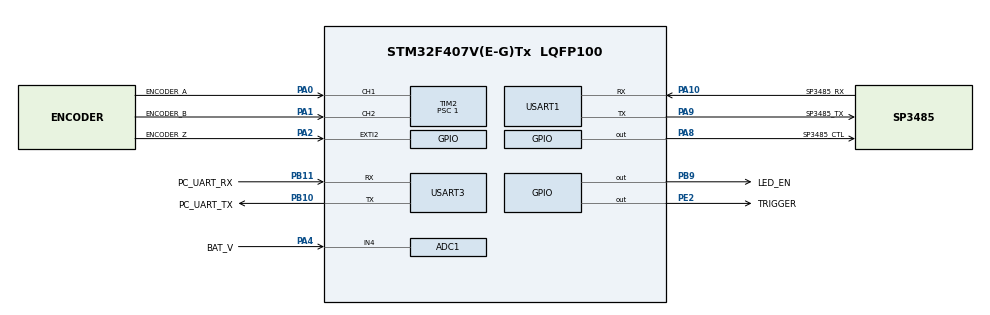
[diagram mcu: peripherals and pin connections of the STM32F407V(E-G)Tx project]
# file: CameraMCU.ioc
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ADC1.Channel-0\#ChannelRegularConversion=ADC_CHANNEL_4
ADC1.NbrOfConversionFlag=1
ADC1.Rank-0\#ChannelRegularConversion=1
ADC1.SamplingTime-0\#ChannelRegularConversion=ADC_SAMPLETIME_3CYCLES
ADC1.master=1
Dma.Request0=USART1_RX
Dma.Request1=USART3_RX
Dma.Request2=USART3_TX
Dma.Request3=USART1_TX
Dma.USART1_RX.0.Direction=DMA_PERIPH_TO_MEMORY
Dma.USART1_RX.0.FIFOMode=DMA_FIFOMODE_DISABLE
Dma.USART1_RX.0.Instance=DMA2_Stream2
Dma.USART1_RX.0.MemDataAlignment=DMA_MDATAALIGN_BYTE
Dma.USART1_RX.0.MemInc=DMA_MINC_ENABLE
Dma.USART1_RX.0.Mode=DMA_NORMAL
Dma.USART1_RX.0.PeriphDataAlignment=DMA_PDATAALIGN_BYTE
Dma.USART1_RX.0.PeriphInc=DMA_PINC_DISABLE
Dma.USART1_RX.0.Priority=DMA_PRIORITY_MEDIUM
Dma.USART1_TX.3.Direction=DMA_MEMORY_TO_PERIPH
Dma.USART1_TX.3.FIFOMode=DMA_FIFOMODE_DISABLE
Dma.USART1_TX.3.Instance=DMA2_Stream7
Dma.USART1_TX.3.MemDataAlignment=DMA_MDATAALIGN_BYTE
Dma.USART1_TX.3.MemInc=DMA_MINC_ENABLE
Dma.USART1_TX.3.Mode=DMA_NORMAL
Dma.USART1_TX.3.PeriphDataAlignment=DMA_PDATAALIGN_BYTE
Dma.USART1_TX.3.PeriphInc=DMA_PINC_DISABLE
Dma.USART1_TX.3.Priority=DMA_PRIORITY_LOW
Dma.USART3_RX.1.Direction=DMA_PERIPH_TO_MEMORY
Dma.USART3_RX.1.FIFOMode=DMA_FIFOMODE_DISABLE
Dma.USART3_RX.1.Instance=DMA1_Stream1
Dma.USART3_RX.1.MemDataAlignment=DMA_MDATAALIGN_BYTE
Dma.USART3_RX.1.MemInc=DMA_MINC_ENABLE
Dma.USART3_RX.1.Mode=DMA_NORMAL
Dma.USART3_RX.1.PeriphDataAlignment=DMA_PDATAALIGN_BYTE
Dma.USART3_RX.1.PeriphInc=DMA_PINC_DISABLE
Dma.USART3_RX.1.Priority=DMA_PRIORITY_LOW
Dma.USART3_TX.2.Direction=DMA_MEMORY_TO_PERIPH
Dma.USART3_TX.2.FIFOMode=DMA_FIFOMODE_DISABLE
Dma.USART3_TX.2.Instance=DMA1_Stream3
Dma.USART3_TX.2.MemDataAlignment=DMA_MDATAALIGN_BYTE
Dma.USART3_TX.2.MemInc=DMA_MINC_ENABLE
Dma.USART3_TX.2.Mode=DMA_NORMAL
Dma.USART3_TX.2.PeriphDataAlignment=DMA_PDATAALIGN_BYTE
Dma.USART3_TX.2.PeriphInc=DMA_PINC_DISABLE
Dma.USART3_TX.2.Priority=DMA_PRIORITY_LOW
FREERTOS.CountingSemaphores01=TriggerCount,16,Dynamic,NULL
FREERTOS.Queues01=commondQueue,10,uint32_t,0,Dynamic,NULL,NULL
FREERTOS.Tasks01=BatteryWarning,0,128,BatteryWarning_Task,Default,NULL,Dynamic,NULL,NULL;StartTrigger,0,128,StartTrigger_Task,Default,NULL,Dynamic,NULL,NULL;PCControl,0,256,PCControl_Task,Default,NULL,Dynamic,NULL,NULL;LightPWM,0,128,LightPWM_Task,Default,NULL,Dynamic,NULL,NULL
FREERTOS.configENABLE_FPU=1
FREERTOS.configTOTAL_HEAP_SIZE=16800
FREERTOS.configUSE_COUNTING_SEMAPHORES=1
FREERTOS.configUSE_NEWLIB_REENTRANT=1
FREERTOS.configUSE_TIMERS=1
Mcu.Family=STM32F4
Mcu.Name=STM32F407V(E-G)Tx
Mcu.Package=LQFP100
NVIC.DMA1_Stream1_IRQn=true\:5\:0\:false\:false\:true\:true\:false\:true\:true
NVIC.DMA1_Stream3_IRQn=true\:5\:0\:false\:false\:true\:true\:false\:true\:true
NVIC.DMA2_Stream2_IRQn=true\:5\:0\:false\:false\:true\:true\:false\:true\:true
NVIC.DMA2_Stream7_IRQn=true\:5\:0\:false\:false\:true\:true\:false\:true\:true
NVIC.PriorityGroup=NVIC_PRIORITYGROUP_4
NVIC.TIM2_IRQn=true\:5\:0\:true\:false\:true\:true\:true\:true\:true
NVIC.TIM8_TRG_COM_TIM14_IRQn=true\:15\:0\:false\:false\:true\:false\:false\:true\:true
NVIC.TimeBase=TIM8_TRG_COM_TIM14_IRQn
NVIC.TimeBaseIP=TIM14
NVIC.USART1_IRQn=true\:5\:0\:false\:false\:true\:true\:true\:true\:true
NVIC.USART3_IRQn=true\:5\:0\:false\:false\:true\:true\:true\:true\:true
PA0-WKUP.GPIO_Label=ENCODER_A
PA0-WKUP.GPIO_ModeDefaultPP=GPIO_MODE_AF_OD
PA0-WKUP.GPIO_PuPd=GPIO_NOPULL
PA0-WKUP.Signal=S_TIM2_CH1_ETR
PA1.GPIO_Label=ENCODER_B
PA1.GPIO_ModeDefaultPP=GPIO_MODE_AF_OD
PA1.GPIO_PuPd=GPIO_NOPULL
PA1.Signal=S_TIM2_CH2
PA10.GPIO_Label=SP3485_RX
PA10.Mode=Asynchronous
PA10.Signal=USART1_RX
PA13.Mode=Serial_Wire
PA13.Signal=SYS_JTMS-SWDIO
PA14.Mode=Serial_Wire
PA14.Signal=SYS_JTCK-SWCLK
PA2.GPIO_Label=ENCODER_Z
PA2.Signal=GPXTI2
PA4.GPIO_Label=BAT_V
PA4.Signal=ADCx_IN4
PA8.GPIO_Label=SP3485_CTL
PA8.Signal=GPIO_Output
PA9.GPIO_Label=SP3485_TX
PA9.Mode=Asynchronous
PA9.Signal=USART1_TX
PB10.GPIO_Label=PC_UART_TX
PB10.Mode=Asynchronous
PB10.Signal=USART3_TX
PB11.GPIO_Label=PC_UART_RX
PB11.Mode=Asynchronous
PB11.Signal=USART3_RX
PB9.GPIO_Label=LED_EN
PB9.Signal=GPIO_Output
PE2.GPIO_Label=TRIGGER
PE2.Signal=GPIO_Output
PH0-OSC_IN.Mode=HSE-External-Oscillator
PH0-OSC_IN.Signal=RCC_OSC_IN
PH1-OSC_OUT.Mode=HSE-External-Oscillator
PH1-OSC_OUT.Signal=RCC_OSC_OUT
ProjectManager.HeapSize=0x200
ProjectManager.StackSize=0x400
ProjectManager.TargetToolchain=STM32CubeIDE
RCC.48MHZClocksFreq_Value=84000000
RCC.AHBFreq_Value=168000000
RCC.APB1CLKDivider=RCC_HCLK_DIV4
RCC.APB1Freq_Value=42000000
RCC.APB1TimFreq_Value=84000000
RCC.APB2CLKDivider=RCC_HCLK_DIV2
RCC.APB2Freq_Value=84000000
RCC.APB2TimFreq_Value=168000000
RCC.CortexFreq_Value=168000000
RCC.HCLKFreq_Value=168000000
RCC.HSE_VALUE=8000000
RCC.HSI_VALUE=16000000
RCC.LSE_VALUE=32768
RCC.PLLM=4
RCC.PLLN=168
RCC.PLLSourceVirtual=RCC_PLLSOURCE_HSE
RCC.SYSCLKFreq_VALUE=168000000
RCC.SYSCLKSource=RCC_SYSCLKSOURCE_PLLCLK
RCC.VCOOutputFreq_Value=336000000
SH.ADCx_IN4.0=ADC1_IN4,IN4
SH.S_TIM2_CH1_ETR.0=TIM2_CH1,Encoder_Interface
SH.S_TIM2_CH2.0=TIM2_CH2,Encoder_Interface
TIM2.AutoReloadPreload=TIM_AUTORELOAD_PRELOAD_ENABLE
TIM2.CounterMode=TIM_COUNTERMODE_UP
TIM2.EncoderMode=TIM_ENCODERMODE_TI12
TIM2.IC1Filter=0
TIM2.IC2Filter=0
TIM2.IC2Polarity=TIM_ICPOLARITY_RISING
TIM2.Period=500
TIM2.Prescaler=1
TIM2.TIM_MasterOutputTrigger=TIM_TRGO_RESET
USART1.VirtualMode=VM_ASYNC
USART3.VirtualMode=VM_ASYNC
VP_FREERTOS_VS_CMSIS_V1.Mode=CMSIS_V1
VP_SYS_VS_tim14.Mode=TIM14
board=custom

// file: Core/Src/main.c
/* USER CODE BEGIN Header */
/**
  ******************************************************************************
  * @file           : main.c
  * @brief          : Main program body
  ******************************************************************************
  * @attention
  *
  * Copyright (c) 2024 STMicroelectronics.
  * All rights reserved.
  *
  * This software is licensed under terms that can be found in the LICENSE file
  * in the root directory of this software component.
  * If no LICENSE file comes with this software, it is provided AS-IS.
  *
  ******************************************************************************
  */
/* USER CODE END Header */
#include "main.h"
#include "cmsis_os.h"
#include "adc.h"
#include "dma.h"
#include "tim.h"
#include "usart.h"
#include "gpio.h"

/* USER CODE BEGIN PTD */
extern osThreadId StartTriggerHandle;
uint8_t isConnect = 0;
/* USER CODE END PTD */

void SystemClock_Config(void);

void MX_FREERTOS_Init(void);

/* USER CODE BEGIN PFP */
uint8_t PC_RX_BUFFER[50];
/* USER CODE END PFP */

int main(void) {

    /* MCU Configuration--------------------------------------------------------*/

    /* Reset of all peripherals, Initializes the Flash interface and the Systick. */
    HAL_Init();

    /* Configure the system clock */
    SystemClock_Config();

    /* Initialize all configured peripherals */
    MX_GPIO_Init();
    MX_DMA_Init();
    MX_ADC1_Init();
    MX_TIM2_Init();
    MX_USART1_UART_Init();
    MX_USART3_UART_Init();
    /* USER CODE BEGIN 2 */
    HAL_GPIO_WritePin(SP3485_CTL_GPIO_Port, SP3485_CTL_Pin, GPIO_PIN_RESET);

    /* USER CODE END 2 */

    /* Call init function for freertos objects (in cmsis_os2.c) */
    MX_FREERTOS_Init();

    /* Start scheduler */
    osKernelStart();

    /* We should never get here as control is now taken by the scheduler */

    /* Infinite loop */
    while (1) {

        /* USER CODE BEGIN 3 */

    }
#if 0
    /* USER CODE END 3 */
  }

  /**
    * @brief System Clock Configuration
    * @retval None
    */
  void SystemClock_Config(void)
  {
    RCC_OscInitTypeDef RCC_OscInitStruct = {0};
    RCC_ClkInitTypeDef RCC_ClkInitStruct = {0};

    /** Configure the main internal regulator output voltage
    */
    __HAL_RCC_PWR_CLK_ENABLE();
    __HAL_PWR_VOLTAGESCALING_CONFIG(PWR_REGULATOR_VOLTAGE_SCALE1);

    /** Initializes the RCC Oscillators according to the specified parameters
    * in the RCC_OscInitTypeDef structure.
    */
    RCC_OscInitStruct.OscillatorType = RCC_OSCILLATORTYPE_HSE;
    RCC_OscInitStruct.HSEState = RCC_HSE_ON;
    RCC_OscInitStruct.PLL.PLLState = RCC_PLL_ON;
    RCC_OscInitStruct.PLL.PLLSource = RCC_PLLSOURCE_HSE;
    RCC_OscInitStruct.PLL.PLLM = 4;
    RCC_OscInitStruct.PLL.PLLN = 168;
    RCC_OscInitStruct.PLL.PLLP = RCC_PLLP_DIV2;
    RCC_OscInitStruct.PLL.PLLQ = 7;
    if (HAL_RCC_OscConfig(&RCC_OscInitStruct) != HAL_OK)
    {
      Error_Handler();
    }

    /** Initializes the CPU, AHB and APB buses clocks
    */
    RCC_ClkInitStruct.ClockType = RCC_CLOCKTYPE_HCLK|RCC_CLOCKTYPE_SYSCLK
                                |RCC_CLOCKTYPE_PCLK1|RCC_CLOCKTYPE_PCLK2;
    RCC_ClkInitStruct.SYSCLKSource = RCC_SYSCLKSOURCE_PLLCLK;
    RCC_ClkInitStruct.AHBCLKDivider = RCC_SYSCLK_DIV1;
    RCC_ClkInitStruct.APB1CLKDivider = RCC_HCLK_DIV4;
    RCC_ClkInitStruct.APB2CLKDivider = RCC_HCLK_DIV2;

    if (HAL_RCC_ClockConfig(&RCC_ClkInitStruct, FLASH_LATENCY_5) != HAL_OK)
    {
      Error_Handler();
    }
  }

  /* USER CODE BEGIN 4 */
#else
}

/**
  * @brief System Clock Configuration
  * @retval None
  */
void SystemClock_Config(void) {
    RCC_OscInitTypeDef RCC_OscInitStruct = {0};
    RCC_ClkInitTypeDef RCC_ClkInitStruct = {0};

    /** Configure the main internal regulator output voltage
    */
    __HAL_RCC_PWR_CLK_ENABLE();
    __HAL_PWR_VOLTAGESCALING_CONFIG(PWR_REGULATOR_VOLTAGE_SCALE1);
    RCC_ClkInitStruct.ClockType = RCC_CLOCKTYPE_HCLK | RCC_CLOCKTYPE_SYSCLK
                                  | RCC_CLOCKTYPE_PCLK1 | RCC_CLOCKTYPE_PCLK2;
    RCC_ClkInitStruct.SYSCLKSource = RCC_SYSCLKSOURCE_HSI;
    RCC_ClkInitStruct.AHBCLKDivider = RCC_SYSCLK_DIV1;
    RCC_ClkInitStruct.APB1CLKDivider = RCC_HCLK_DIV4;
    RCC_ClkInitStruct.APB2CLKDivider = RCC_HCLK_DIV2;

    if (HAL_RCC_ClockConfig(&RCC_ClkInitStruct, FLASH_LATENCY_5) != HAL_OK) {
        Error_Handler();
    }
    /** Initializes the RCC Oscillators according to the specified parameters
    * in the RCC_OscInitTypeDef structure.
    */
    RCC_OscInitStruct.OscillatorType = RCC_OSCILLATORTYPE_HSE;
    RCC_OscInitStruct.HSEState = RCC_HSE_ON;
    RCC_OscInitStruct.PLL.PLLState = RCC_PLL_ON;
    RCC_OscInitStruct.PLL.PLLSource = RCC_PLLSOURCE_HSE;
    RCC_OscInitStruct.PLL.PLLM = 4;
    RCC_OscInitStruct.PLL.PLLN = 168;
    RCC_OscInitStruct.PLL.PLLP = RCC_PLLP_DIV2;
    RCC_OscInitStruct.PLL.PLLQ = 7;
    if (HAL_RCC_OscConfig(&RCC_OscInitStruct) != HAL_OK) {
        Error_Handler();
    }

    /** Initializes the CPU, AHB and APB buses clocks
    */
    RCC_ClkInitStruct.ClockType = RCC_CLOCKTYPE_HCLK | RCC_CLOCKTYPE_SYSCLK
                                  | RCC_CLOCKTYPE_PCLK1 | RCC_CLOCKTYPE_PCLK2;
    RCC_ClkInitStruct.SYSCLKSource = RCC_SYSCLKSOURCE_PLLCLK;
    RCC_ClkInitStruct.AHBCLKDivider = RCC_SYSCLK_DIV1;
    RCC_ClkInitStruct.APB1CLKDivider = RCC_HCLK_DIV4;
    RCC_ClkInitStruct.APB2CLKDivider = RCC_HCLK_DIV2;

    if (HAL_RCC_ClockConfig(&RCC_ClkInitStruct, FLASH_LATENCY_5) != HAL_OK) {
        Error_Handler();
    }
}

#endif
/* USER CODE END 4 */

void HAL_TIM_PeriodElapsedCallback(TIM_HandleTypeDef *htim) {
    if (htim->Instance == TIM14) {
        HAL_IncTick();
    }
    /* USER CODE BEGIN Callback 1 */
    if (htim->Instance == TIM2) {
        BaseType_t xHigherPriorityTaskWoken = pdFALSE;
        vTaskNotifyGiveFromISR(StartTriggerHandle, &xHigherPriorityTaskWoken);
    }
    /* USER CODE END Callback 1 */
}

void Error_Handler(void) {
    __disable_irq();
    while (1) {
    }
}

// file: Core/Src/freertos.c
/* USER CODE BEGIN Header */
/**
  ******************************************************************************
  * File Name          : freertos.c
  * Description        : Code for freertos applications
  ******************************************************************************
  * @attention
  *
  * Copyright (c) 2024 STMicroelectronics.
  * All rights reserved.
  *
  * This software is licensed under terms that can be found in the LICENSE file
  * in the root directory of this software component.
  * If no LICENSE file comes with this software, it is provided AS-IS.
  *
  ******************************************************************************
  */
/* USER CODE END Header */

#include "FreeRTOS.h"
#include "task.h"
#include "main.h"
#include "cmsis_os.h"

/* USER CODE BEGIN Includes */
#include "tim.h"
#include "log.h"
#include "usart.h"
#include "crc16.h"
/* USER CODE END Includes */

/* USER CODE BEGIN PTD */
uint16_t trigger_spac;
uint16_t trigger_time;
uint8_t light_PWM;
extern struct SYSTEM_COMMOND comBuffer;
/* USER CODE END PTD */

/* USER CODE BEGIN PM */

struct SYS_Config {
    enum SYS_Status {
        SETTING = 0,
        RUNNING,
        STOP
    } sysStatus;
    enum Trigger_Mode {
        Soft = 0,
        Hard
    } triggerMode;
} sysConfig;
/* USER CODE END PM */

/* USER CODE BEGIN Variables */
uint8_t ledtime;
/* USER CODE END Variables */
osThreadId BatteryWarningHandle;
osThreadId StartTriggerHandle;
osThreadId PCControlHandle;
osThreadId LightPWMHandle;
osMessageQId commondQueueHandle;
osSemaphoreId TriggerCountHandle;

/* USER CODE BEGIN FunctionPrototypes */
union {
    uint16_t Data;
    struct {
        uint8_t id;
        uint8_t mot;
        uint8_t dir;
    } B;
} ControlData;//速度模式
static uint8_t Len_ControlBuffer[10];

void LEN_Control(uint8_t id, uint8_t mot, uint8_t dir) {
    *(uint32_t *) (Len_ControlBuffer) = 0xFFEEFEEF;
    Len_ControlBuffer[4] = id;
    Len_ControlBuffer[5] = mot;
    Len_ControlBuffer[6] = dir;
//    uint16_t crc = Get_Crc16(Len_ControlBuffer + 4, 3);
//    *(uint16_t *) (Len_ControlBuffer + 7) = crc;
    HAL_GPIO_WritePin(SP3485_CTL_GPIO_Port, SP3485_CTL_Pin, GPIO_PIN_SET);
    HAL_UART_Transmit_DMA(&huart1, Len_ControlBuffer, 7);
}

/* USER CODE END FunctionPrototypes */

void BatteryWarning_Task(void const *argument);

void StartTrigger_Task(void const *argument);

void PCControl_Task(void const *argument);

void LightPWM_Task(void const *argument);

void MX_FREERTOS_Init(void); /* (MISRA C 2004 rule 8.1) */

/* GetIdleTaskMemory prototype (linked to static allocation support) */
void vApplicationGetIdleTaskMemory(StaticTask_t **ppxIdleTaskTCBBuffer, StackType_t **ppxIdleTaskStackBuffer,
                                   uint32_t *pulIdleTaskStackSize);

/* GetTimerTaskMemory prototype (linked to static allocation support) */
void vApplicationGetTimerTaskMemory(StaticTask_t **ppxTimerTaskTCBBuffer, StackType_t **ppxTimerTaskStackBuffer,
                                    uint32_t *pulTimerTaskStackSize);

/* USER CODE BEGIN GET_IDLE_TASK_MEMORY */
static StaticTask_t xIdleTaskTCBBuffer;
static StackType_t xIdleStack[configMINIMAL_STACK_SIZE];

void vApplicationGetIdleTaskMemory(StaticTask_t **ppxIdleTaskTCBBuffer, StackType_t **ppxIdleTaskStackBuffer,
                                   uint32_t *pulIdleTaskStackSize) {
    *ppxIdleTaskTCBBuffer = &xIdleTaskTCBBuffer;
    *ppxIdleTaskStackBuffer = &xIdleStack[0];
    *pulIdleTaskStackSize = configMINIMAL_STACK_SIZE;
    /* place for user code */
}
/* USER CODE END GET_IDLE_TASK_MEMORY */

/* USER CODE BEGIN GET_TIMER_TASK_MEMORY */
static StaticTask_t xTimerTaskTCBBuffer;
static StackType_t xTimerStack[configTIMER_TASK_STACK_DEPTH];

void vApplicationGetTimerTaskMemory(StaticTask_t **ppxTimerTaskTCBBuffer, StackType_t **ppxTimerTaskStackBuffer,
                                    uint32_t *pulTimerTaskStackSize) {
    *ppxTimerTaskTCBBuffer = &xTimerTaskTCBBuffer;
    *ppxTimerTaskStackBuffer = &xTimerStack[0];
    *pulTimerTaskStackSize = configTIMER_TASK_STACK_DEPTH;
    /* place for user code */
}
/* USER CODE END GET_TIMER_TASK_MEMORY */

void MX_FREERTOS_Init(void) {
    /* USER CODE BEGIN Init */
    light_PWM = 0;
    trigger_time = 10;
    sysConfig.triggerMode = Hard;
    sysConfig.sysStatus = STOP;
    /* USER CODE END Init */

    /* Create the semaphores(s) */
    /* definition and creation of TriggerCount */
    osSemaphoreDef(TriggerCount);
    TriggerCountHandle = osSemaphoreCreate(osSemaphore(TriggerCount), 16);

    /* Create the queue(s) */
    /* definition and creation of commondQueue */
    osMessageQDef(commondQueue, 10, uint32_t);
    commondQueueHandle = osMessageCreate(osMessageQ(commondQueue), NULL);

    /* Create the thread(s) */
    /* definition and creation of BatteryWarning */
    osThreadDef(BatteryWarning, BatteryWarning_Task, osPriorityNormal, 0, 128);
    BatteryWarningHandle = osThreadCreate(osThread(BatteryWarning), NULL);

    /* definition and creation of StartTrigger */
    osThreadDef(StartTrigger, StartTrigger_Task, osPriorityNormal, 0, 128);
    StartTriggerHandle = osThreadCreate(osThread(StartTrigger), NULL);

    /* definition and creation of PCControl */
    osThreadDef(PCControl, PCControl_Task, osPriorityNormal, 0, 256);
    PCControlHandle = osThreadCreate(osThread(PCControl), NULL);

    /* definition and creation of LightPWM */
    osThreadDef(LightPWM, LightPWM_Task, osPriorityNormal, 0, 128);
    LightPWMHandle = osThreadCreate(osThread(LightPWM), NULL);

}

void BatteryWarning_Task(void const *argument) {
    for (;;) {
        osDelay(1);
    }
}

void StartTrigger_Task(void const *argument) {
    /* USER CODE BEGIN StartTrigger_Task */
    HAL_TIM_Encoder_Start(&htim2, TIM_CHANNEL_ALL);
    HAL_TIM_Base_Start_IT(&htim2);
    vTaskSuspend(StartTriggerHandle);
    /* Infinite loop */
    for (;;) {
        ulTaskNotifyTake(pdTRUE, portMAX_DELAY);
        if (sysConfig.triggerMode == Hard) {
            HAL_GPIO_WritePin(TRIGGER_GPIO_Port, TRIGGER_Pin, GPIO_PIN_SET);
        }
        HAL_GPIO_WritePin(LED_EN_GPIO_Port, LED_EN_Pin, GPIO_PIN_SET);
        osDelay(trigger_time);
        if (sysConfig.triggerMode == Hard) {
            HAL_GPIO_WritePin(TRIGGER_GPIO_Port, TRIGGER_Pin, GPIO_PIN_RESET);
        }
        HAL_GPIO_WritePin(LED_EN_GPIO_Port, LED_EN_Pin, GPIO_PIN_RESET);
        osDelay(1);

    }
    /* USER CODE END StartTrigger_Task */
}

void PCControl_Task(void const *argument) {
    /* USER CODE BEGIN PCControl_Task */
    /* Infinite loop */
    for (;;) {
        ulTaskNotifyTake(pdTRUE, portMAX_DELAY);
        switch (comBuffer.type) {
            case LEN:
                LEN_Control(comBuffer.Data.len.id, comBuffer.Data.len.mot, comBuffer.Data.len.dir);
                break;
            case SYSTEM:
                if (comBuffer.Data.system.witch == 0x01) {
                    trigger_time = comBuffer.Data.system.num;
                } else if (comBuffer.Data.system.witch == 0x02) {
                    TIM2->ARR = comBuffer.Data.system.num;
                } else if (comBuffer.Data.system.witch == 0x03) {
                    if (comBuffer.Data.system.num >= 0 && comBuffer.Data.system.num < 10) {
                        light_PWM = comBuffer.Data.system.num;
                    }
                } else if (comBuffer.Data.system.witch == 0x04) {
                    if (comBuffer.Data.system.num == 0x0001) {
                        sysConfig.triggerMode = Soft;
                    } else if (comBuffer.Data.system.num == 0x1000) {
                        sysConfig.triggerMode = Hard;
                    }
                }
                break;
            case STATUS:
                if (comBuffer.Data.status.status_flag == 0x01) {
                    sysConfig.sysStatus = SETTING;
                    vTaskResume(LightPWMHandle);
                    vTaskSuspend(StartTriggerHandle);
                } else if (comBuffer.Data.status.status_flag == 0x02) {
                    sysConfig.sysStatus = RUNNING;
                    vTaskSuspend(LightPWMHandle);
                    vTaskResume(StartTriggerHandle);
                } else if (comBuffer.Data.status.status_flag == 0x03) {
                    sysConfig.sysStatus = STOP;
                    HAL_GPIO_WritePin(LED_EN_GPIO_Port, LED_EN_Pin, GPIO_PIN_RESET);
                    vTaskSuspend(LightPWMHandle);
                    vTaskSuspend(StartTriggerHandle);
                }
                break;
        }
        osDelay(1);
    }
    /* USER CODE END PCControl_Task */
}

void LightPWM_Task(void const *argument) {
    /* USER CODE BEGIN LightPWM_Task */
    /* Infinite loop */
    vTaskSuspend(LightPWMHandle);
    for (;;) {
        if (light_PWM > 0) {
            HAL_GPIO_WritePin(LED_EN_GPIO_Port, LED_EN_Pin, GPIO_PIN_SET);
            osDelay(light_PWM);
        }
        HAL_GPIO_WritePin(LED_EN_GPIO_Port, LED_EN_Pin, GPIO_PIN_RESET);
        osDelay(10 - light_PWM);
    }
    /* USER CODE END LightPWM_Task */
}
